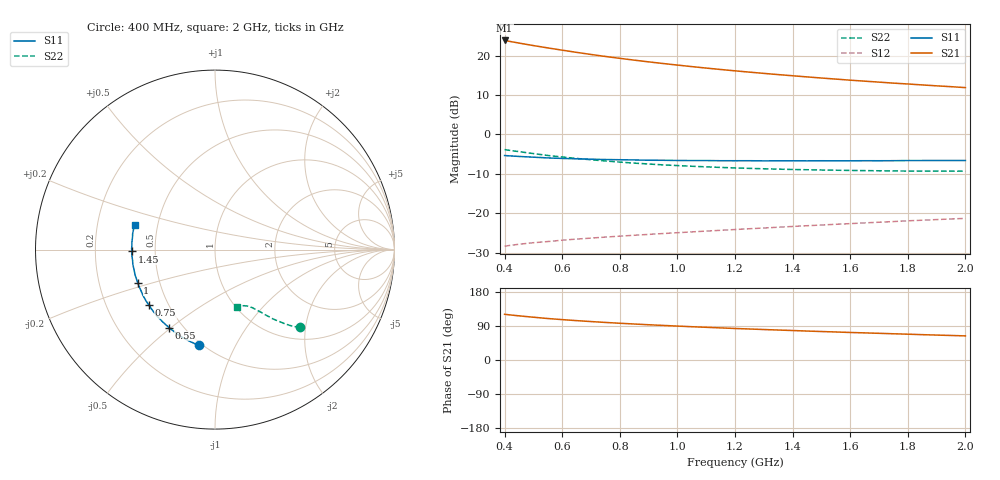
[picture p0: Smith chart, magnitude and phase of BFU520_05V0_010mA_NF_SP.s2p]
! Filename:  P:\Prog\Test\Noise\ATS_data\Testdata_Net\06 Compressed Noise after Statistics\BFU520_APG2013_37_A05_05p0V_010mA_NF_CM01_D.sf
! Date/Time: Fri 26/Apr/2013 14:13:11
! BFU520_APG2013_37_A05_05p0V_1to20mA_NF_CM01_Bias6_R.sf
! Noise Parameter Data File
! BFU520_APG2013_37_A05_05p0V_1to20mA_NF_CM01
! Date/time: Tue Apr 23 16:46:24 2013
! VAR V_out= 5.000000
! VAR I_out= 9.990000
! VAR V_in= 0.838700
! VAR I_in= 0.114405
! Device data file deembeded for feedlines and parallel
! Original file: \06 Compressed Noise after Statistics\BFU520_APG2013_37_A05_05p0V_010mA_NF_CM01_R.sf
! Feed-files: PR047V01_250413_Feed1.s2p, PR047V01_250413_Feed2.s2p
! Parallel-file: PR047V01_250413_Par.s2p
# MHz S MA R 50
!  Freq-MHz  S11-mag  S11-arg  S21-mag  S21-arg  S12-mag  S12-arg  S22-mag  S22-arg
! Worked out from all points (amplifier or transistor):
!   37 points, 400 MHz to 2 GHz, reference 50 ohm
!   highest |S21| = 23.8 dB at 400 MHz (marker M1)
!   |S21| within 3 dB of that: start of sweep to 648.2 MHz
!   unconditionally stable (mu >= 1): 1.746 GHz to end of sweep
!   at 500 MHz: K = 0.48, MSG = 25.0 dB, |S12| = -27.4 dB
!   at 1.1 GHz: K = 0.83, MSG = 20.7 dB, |S12| = -24.5 dB
!   at 2 GHz: K = 1.04, MAG = 15.4 dB, |S12| = -21.3 dB
!   lowest NFmin = 0.84 dB at 440 MHz
!   S11 on the Smith chart (normalised r, x): 400 MHz: 0.48, -0.72; 550 MHz: 0.42, -0.49; 750 MHz: 0.39, -0.32; 1 GHz: 0.38, -0.18; 1.45 GHz: 0.37, -0.01; 2 GHz: 0.37, +0.13
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400  0.5405 -99.5  15.54 120.6  0.03842 52.7  0.6431 -42.4
433  0.5313 -104.6  14.77 117.9  0.03989 51.7  0.6178 -43.9
460  0.5244 -108.5  14.19 115.8  0.04101 51.0  0.5996 -45.1
500  0.5156 -114.0  13.39 112.9  0.04249 50.1  0.573 -46.5
550  0.5047 -120.5  12.51 109.4  0.04396 49.2  0.5419 -47.9
600  0.4971 -125.9  11.71 106.6  0.04573 48.8  0.5186 -49.2
650  0.4916 -131.0  10.98 103.9  0.04726 48.3  0.497 -50.5
700  0.4862 -135.4  10.33 101.4  0.04863 48.1  0.4779 -51.3
750  0.4813 -139.9  9.748 99.1  0.05007 48.1  0.4616 -52.2
800  0.4787 -143.7  9.224 97.0  0.05146 48.1  0.4466 -53.0
850  0.4757 -147.4  8.753 95.0  0.05282 48.1  0.4336 -53.7
900  0.4717 -151.0  8.321 93.0  0.05416 48.3  0.4225 -54.5
950  0.4709 -154.1  7.934 91.2  0.05552 48.5  0.412 -55.1
1000  0.4684 -156.9  7.577 89.5  0.05691 48.7  0.4035 -55.6
1050  0.4669 -160.2  7.247 87.8  0.05826 48.8  0.3958 -56.4
1200  0.4647 -167.8  6.406 83.2  0.06243 49.5  0.3768 -58.2
1300  0.463 -172.3  5.946 80.4  0.06531 50.1  0.3676 -59.4
1450  0.4632 -178.8  5.366 76.4  0.06974 50.7  0.3574 -61.3
1500  0.4646 179.5  5.194 75.1  0.07121 50.9  0.3548 -62.0
1600  0.464 175.6  4.878 72.7  0.07419 51.2  0.3502 -63.4
1750  0.4654 170.4  4.475 69.2  0.07878 51.7  0.3448 -65.4
2000  0.4679 162.9  3.926 63.6  0.08633 52.1  0.3425 -69.3
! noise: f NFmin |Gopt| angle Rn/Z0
400  0.9487  0.01215  134.3  0.1159
460  0.8669  0.0582  168.4  0.0961
600  0.9488  0.03887  147.8  0.1077
800  0.9504  0.08128  159.9  0.0943
1000  0.9502  0.09867  162.9  0.0914
1200  0.972  0.1126  166.9  0.0945
1400  1.006  0.1374  167.9  0.0888
1600  1.031  0.1489  174.2  0.0884
1800  1.012  0.1688  179.3  0.0852
2000  1.081  0.1838  -175.2  0.0906
